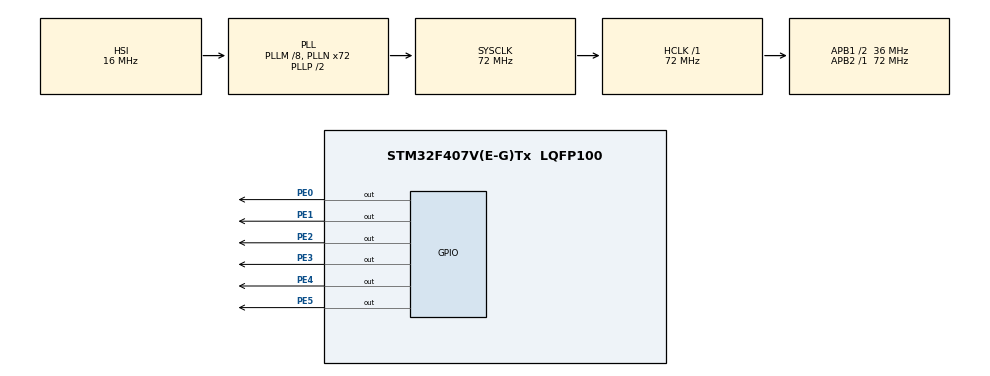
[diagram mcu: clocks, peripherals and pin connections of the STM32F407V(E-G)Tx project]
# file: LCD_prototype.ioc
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Mcu.Family=STM32F4
Mcu.Name=STM32F407V(E-G)Tx
Mcu.Package=LQFP100
NVIC.PriorityGroup=NVIC_PRIORITYGROUP_4
PE0.Signal=GPIO_Output
PE1.Signal=GPIO_Output
PE2.Signal=GPIO_Output
PE3.Signal=GPIO_Output
PE4.Signal=GPIO_Output
PE5.Signal=GPIO_Output
PH0-OSC_IN.Mode=HSE-External-Oscillator
PH0-OSC_IN.Signal=RCC_OSC_IN
PH1-OSC_OUT.Mode=HSE-External-Oscillator
PH1-OSC_OUT.Signal=RCC_OSC_OUT
ProjectManager.HeapSize=0x200
ProjectManager.StackSize=0x400
ProjectManager.TargetToolchain=STM32CubeIDE
RCC.48MHZClocksFreq_Value=36000000
RCC.AHBFreq_Value=72000000
RCC.APB1CLKDivider=RCC_HCLK_DIV2
RCC.APB1Freq_Value=36000000
RCC.APB1TimFreq_Value=72000000
RCC.APB2Freq_Value=72000000
RCC.APB2TimFreq_Value=72000000
RCC.CortexFreq_Value=72000000
RCC.HCLKFreq_Value=72000000
RCC.HSE_VALUE=25000000
RCC.HSI_VALUE=16000000
RCC.LSE_VALUE=32768
RCC.PLLM=8
RCC.PLLN=72
RCC.SYSCLKFreq_VALUE=72000000
RCC.SYSCLKSource=RCC_SYSCLKSOURCE_PLLCLK
RCC.VCOOutputFreq_Value=144000000
board=custom

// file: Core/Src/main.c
/* USER CODE BEGIN Header */
/**
  ******************************************************************************
  * @file           : main.c
  * @brief          : Main program body
  ******************************************************************************
  * @attention
  *
  * <h2><center>&copy; Copyright (c) 2021 STMicroelectronics.
  * All rights reserved.</center></h2>
  *
  * This software component is licensed by ST under BSD 3-Clause license,
  * the "License"; You may not use this file except in compliance with the
  * License. You may obtain a copy of the License at:
  *                        opensource.org/licenses/BSD-3-Clause
  *
  ******************************************************************************
  */
/* USER CODE END Header */
#include "main.h"
#include "LCD16x2.h"

void SystemClock_Config(void);
static void MX_GPIO_Init(void);

int main(void)
{

  /* MCU Configuration--------------------------------------------------------*/

  printf("init");
  /* Reset of all peripherals, Initializes the Flash interface and the Systick. */
  HAL_Init();

  /* Configure the system clock */
  SystemClock_Config();

  /* Initialize all configured peripherals */
  MX_GPIO_Init();

  printf("lcd init");
  /* Infinite loop */
  /* USER CODE BEGIN WHILE */
  LCD_Init();
  LCD_Clear();
  LCD_Set_Cursor(1, 1);
  LCD_Write_String("  DeepBlue  ");
  LCD_Set_Cursor(2, 1);
  LCD_Write_String("STM32 Course");

  while (1)
  {
	  printf("running");
      LCD_SR();  HAL_Delay(450);
      LCD_SR();  HAL_Delay(450);
      LCD_SR();  HAL_Delay(450);
      LCD_SR();  HAL_Delay(450);

      LCD_SL();  HAL_Delay(450);
      LCD_SL();  HAL_Delay(450);
      LCD_SL();  HAL_Delay(450);
      LCD_SL();  HAL_Delay(450);
  }
  /* USER CODE END 3 */
}

void SystemClock_Config(void)
{
  RCC_OscInitTypeDef RCC_OscInitStruct = {0};
  RCC_ClkInitTypeDef RCC_ClkInitStruct = {0};

  /** Configure the main internal regulator output voltage
  */
  __HAL_RCC_PWR_CLK_ENABLE();
  __HAL_PWR_VOLTAGESCALING_CONFIG(PWR_REGULATOR_VOLTAGE_SCALE1);
  /** Initializes the RCC Oscillators according to the specified parameters
  * in the RCC_OscInitTypeDef structure.
  */
  RCC_OscInitStruct.OscillatorType = RCC_OSCILLATORTYPE_HSI;
  RCC_OscInitStruct.HSIState = RCC_HSI_ON;
  RCC_OscInitStruct.HSICalibrationValue = RCC_HSICALIBRATION_DEFAULT;
  RCC_OscInitStruct.PLL.PLLState = RCC_PLL_ON;
  RCC_OscInitStruct.PLL.PLLSource = RCC_PLLSOURCE_HSI;
  RCC_OscInitStruct.PLL.PLLM = 8;
  RCC_OscInitStruct.PLL.PLLN = 72;
  RCC_OscInitStruct.PLL.PLLP = RCC_PLLP_DIV2;
  RCC_OscInitStruct.PLL.PLLQ = 4;
  if (HAL_RCC_OscConfig(&RCC_OscInitStruct) != HAL_OK)
  {
    Error_Handler();
  }
  /** Initializes the CPU, AHB and APB buses clocks
  */
  RCC_ClkInitStruct.ClockType = RCC_CLOCKTYPE_HCLK|RCC_CLOCKTYPE_SYSCLK
                              |RCC_CLOCKTYPE_PCLK1|RCC_CLOCKTYPE_PCLK2;
  RCC_ClkInitStruct.SYSCLKSource = RCC_SYSCLKSOURCE_PLLCLK;
  RCC_ClkInitStruct.AHBCLKDivider = RCC_SYSCLK_DIV1;
  RCC_ClkInitStruct.APB1CLKDivider = RCC_HCLK_DIV2;
  RCC_ClkInitStruct.APB2CLKDivider = RCC_HCLK_DIV1;

  if (HAL_RCC_ClockConfig(&RCC_ClkInitStruct, FLASH_LATENCY_2) != HAL_OK)
  {
    Error_Handler();
  }
}

static void MX_GPIO_Init(void)
{
  GPIO_InitTypeDef GPIO_InitStruct = {0};

  /* GPIO Ports Clock Enable */
  __HAL_RCC_GPIOE_CLK_ENABLE();
  __HAL_RCC_GPIOC_CLK_ENABLE();
  __HAL_RCC_GPIOH_CLK_ENABLE();

  /*Configure GPIO pin Output Level */
  HAL_GPIO_WritePin(GPIOE, GPIO_PIN_2|GPIO_PIN_3|GPIO_PIN_4|GPIO_PIN_5
                          |GPIO_PIN_6, GPIO_PIN_RESET);

  /*Configure GPIO pin Output Level */
  HAL_GPIO_WritePin(GPIOC, GPIO_PIN_13, GPIO_PIN_RESET);

  /*Configure GPIO pins : PE2 PE3 PE4 PE5
                           PE6 */
  GPIO_InitStruct.Pin = GPIO_PIN_2|GPIO_PIN_3|GPIO_PIN_4|GPIO_PIN_5
                          |GPIO_PIN_6;
  GPIO_InitStruct.Mode = GPIO_MODE_OUTPUT_PP;
  GPIO_InitStruct.Pull = GPIO_NOPULL;
  GPIO_InitStruct.Speed = GPIO_SPEED_FREQ_LOW;
  HAL_GPIO_Init(GPIOE, &GPIO_InitStruct);

  /*Configure GPIO pin : PC13 */
  GPIO_InitStruct.Pin = GPIO_PIN_13;
  GPIO_InitStruct.Mode = GPIO_MODE_OUTPUT_PP;
  GPIO_InitStruct.Pull = GPIO_NOPULL;
  GPIO_InitStruct.Speed = GPIO_SPEED_FREQ_LOW;
  HAL_GPIO_Init(GPIOC, &GPIO_InitStruct);

}

void Error_Handler(void)
{
  __disable_irq();
  while (1)
  {
  }
}

/************************ (C) COPYRIGHT STMicroelectronics *****END OF FILE****/
